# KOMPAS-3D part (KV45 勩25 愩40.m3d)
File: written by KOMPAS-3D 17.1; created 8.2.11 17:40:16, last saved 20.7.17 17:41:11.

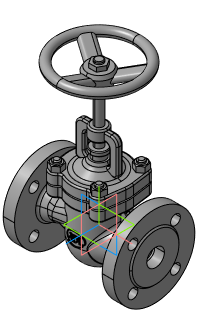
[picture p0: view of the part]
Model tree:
1. Плоскость XY
2. Плоскость ZX
3. Плоскость ZY
4. Ось X
5. Ось Y
6. Ось Z
7. Начало координат
8. Операция без истории:3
